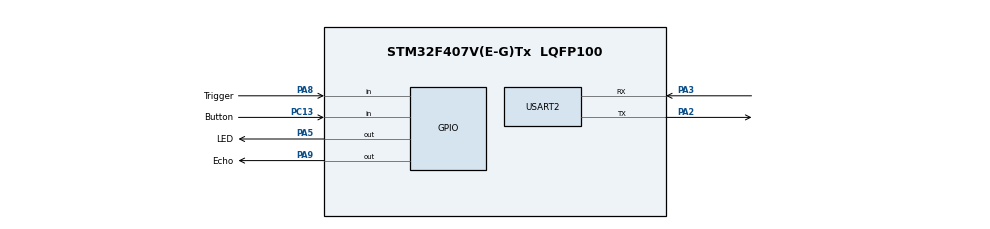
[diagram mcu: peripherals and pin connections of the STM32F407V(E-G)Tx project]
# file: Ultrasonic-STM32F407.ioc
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Mcu.Family=STM32F4
Mcu.Name=STM32F407V(E-G)Tx
Mcu.Package=LQFP100
NVIC.PriorityGroup=NVIC_PRIORITYGROUP_0
PA2.Mode=Asynchronous
PA2.Signal=USART2_TX
PA3.Mode=Asynchronous
PA3.Signal=USART2_RX
PA5.GPIO_Label=LED
PA5.Signal=GPIO_Output
PA8.GPIO_Label=Trigger
PA8.Signal=GPIO_Input
PA9.GPIO_Label=Echo
PA9.Signal=GPIO_Output
PC13-ANTI_TAMP.GPIO_Label=Button
PC13-ANTI_TAMP.Signal=GPIO_Input
ProjectManager.HeapSize=0x200
ProjectManager.StackSize=0x400
ProjectManager.TargetToolchain=STM32CubeIDE
RCC.48MHZClocksFreq_Value=14285714.285714285
RCC.AHBFreq_Value=25000000
RCC.APB1CLKDivider=RCC_HCLK_DIV8
RCC.APB1Freq_Value=3125000
RCC.APB1TimFreq_Value=6250000
RCC.APB2CLKDivider=RCC_HCLK_DIV4
RCC.APB2Freq_Value=6250000
RCC.APB2TimFreq_Value=12500000
RCC.CortexFreq_Value=25000000
RCC.HCLKFreq_Value=25000000
RCC.HSE_VALUE=8000000
RCC.HSI_VALUE=16000000
RCC.PLLM=8
RCC.PLLN=50
RCC.PLLP=RCC_PLLP_DIV4
RCC.PLLQ=7
RCC.SYSCLKFreq_VALUE=25000000
RCC.SYSCLKSource=RCC_SYSCLKSOURCE_PLLCLK
RCC.VCOOutputFreq_Value=100000000
TIM4.Prescaler=24
USART2.VirtualMode=VM_ASYNC
VP_TIM4_VS_ClockSourceINT.Mode=Internal
board=STM32F407G-DISC1

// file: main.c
/* Distance Measurement using Ultrasonic sensor  */

#include "main.h"
#include <string.h>
#include <stdio.h>

#define usTIM	TIM4

TIM_HandleTypeDef htim4;

UART_HandleTypeDef huart2;

#define TRIG_GPIO_Port    GPIOD
#define TRIG_Pin		 GPIO_PIN_0
#define ECHO_GPIO_Port    GPIOD
#define ECHO_Pin 		 GPIO_PIN_0

void SystemClock_Config(void);
static void MX_GPIO_Init(void);
static void MX_TIM4_Init(void);
static void MX_USART2_UART_Init(void);

void usDelay(uint32_t uSec);
//Speed of sound in cm/usec
const float speedOfSound = 0.0343/2;
float distance;

char uartBuf[100];

int main(void)
{

	uint32_t numTicks = 0;

  HAL_Init();

  SystemClock_Config();

  MX_GPIO_Init();
  MX_TIM4_Init();
  MX_USART2_UART_Init();

  while (1)
  {
		//Step 1 Trigger setting low
		HAL_GPIO_WritePin(TRIG_GPIO_Port, TRIG_Pin, GPIO_PIN_RESET);
		usDelay(3);
		//Tigger output sends soundwave 10usec
		HAL_GPIO_WritePin(TRIG_GPIO_Port, TRIG_Pin, GPIO_PIN_SET);
		usDelay(10);

		HAL_GPIO_WritePin(TRIG_GPIO_Port, TRIG_Pin, GPIO_PIN_RESET);

		//Step 2 Wait upto Echo pin reaches High
		while(HAL_GPIO_ReadPin(ECHO_GPIO_Port, ECHO_Pin) == GPIO_PIN_RESET);

		//Step 3 Measuring echo pulse width in usec
		numTicks = 0;
		while(HAL_GPIO_ReadPin(ECHO_GPIO_Port, ECHO_Pin) == GPIO_PIN_SET)
		{
			numTicks++;
			usDelay(2); //2.8usec
		};

		//Step 4 Distance measured in cm
		distance = (numTicks + 0.0f)*2.8*speedOfSound;

		//Step 5 Print distance via uart
		printf(uartBuf, "Distance (cm)  = %.1f\r\n", distance);
		HAL_UART_Transmit(&huart2, (uint8_t *)uartBuf, strlen(uartBuf), 100);

		HAL_Delay(1000);

  }

}

void SystemClock_Config(void)
{
  RCC_OscInitTypeDef RCC_OscInitStruct = {0};
  RCC_ClkInitTypeDef RCC_ClkInitStruct = {0};

  __HAL_RCC_PWR_CLK_ENABLE();
  __HAL_PWR_VOLTAGESCALING_CONFIG(PWR_REGULATOR_VOLTAGE_SCALE2);
  /** Initializes the CPU, AHB and APB busses clocks
  */
  RCC_OscInitStruct.OscillatorType = RCC_OSCILLATORTYPE_HSI;
  RCC_OscInitStruct.HSIState = RCC_HSI_ON;
  RCC_OscInitStruct.HSICalibrationValue = RCC_HSICALIBRATION_DEFAULT;
  RCC_OscInitStruct.PLL.PLLState = RCC_PLL_ON;
  RCC_OscInitStruct.PLL.PLLSource = RCC_PLLSOURCE_HSI;
  RCC_OscInitStruct.PLL.PLLM = 16;
  RCC_OscInitStruct.PLL.PLLN = 336;
  RCC_OscInitStruct.PLL.PLLP = RCC_PLLP_DIV4;
  RCC_OscInitStruct.PLL.PLLQ = 7;
  if (HAL_RCC_OscConfig(&RCC_OscInitStruct) != HAL_OK)
  {
    Error_Handler();
  }
  /** Initializes the CPU, AHB and APB busses clocks
  */
  RCC_ClkInitStruct.ClockType = RCC_CLOCKTYPE_HCLK|RCC_CLOCKTYPE_SYSCLK
                              |RCC_CLOCKTYPE_PCLK1|RCC_CLOCKTYPE_PCLK2;
  RCC_ClkInitStruct.SYSCLKSource = RCC_SYSCLKSOURCE_PLLCLK;
  RCC_ClkInitStruct.AHBCLKDivider = RCC_SYSCLK_DIV1;
  RCC_ClkInitStruct.APB1CLKDivider = RCC_HCLK_DIV2;
  RCC_ClkInitStruct.APB2CLKDivider = RCC_HCLK_DIV1;

  if (HAL_RCC_ClockConfig(&RCC_ClkInitStruct, FLASH_LATENCY_2) != HAL_OK)
  {
    Error_Handler();
  }
}

static void MX_TIM4_Init(void)
{

  TIM_ClockConfigTypeDef sClockSourceConfig = {0};
  TIM_MasterConfigTypeDef sMasterConfig = {0};

  htim4.Instance = TIM4;
  htim4.Init.Prescaler = 84-1;
  htim4.Init.CounterMode = TIM_COUNTERMODE_UP;
  htim4.Init.Period = 0;
  htim4.Init.ClockDivision = TIM_CLOCKDIVISION_DIV1;
  htim4.Init.AutoReloadPreload = TIM_AUTORELOAD_PRELOAD_DISABLE;
  if (HAL_TIM_Base_Init(&htim4) != HAL_OK)
  {
    Error_Handler();
  }
  sClockSourceConfig.ClockSource = TIM_CLOCKSOURCE_INTERNAL;
  if (HAL_TIM_ConfigClockSource(&htim4, &sClockSourceConfig) != HAL_OK)
  {
    Error_Handler();
  }
  sMasterConfig.MasterOutputTrigger = TIM_TRGO_RESET;
  sMasterConfig.MasterSlaveMode = TIM_MASTERSLAVEMODE_DISABLE;
  if (HAL_TIMEx_MasterConfigSynchronization(&htim4, &sMasterConfig) != HAL_OK)
  {
    Error_Handler();
  }

}
static void MX_USART2_UART_Init(void)
{
  huart2.Instance = USART2;
  huart2.Init.BaudRate = 115200;
  huart2.Init.WordLength = UART_WORDLENGTH_8B;
  huart2.Init.StopBits = UART_STOPBITS_1;
  huart2.Init.Parity = UART_PARITY_NONE;
  huart2.Init.Mode = UART_MODE_TX_RX;
  huart2.Init.HwFlowCtl = UART_HWCONTROL_NONE;
  huart2.Init.OverSampling = UART_OVERSAMPLING_16;
  if (HAL_UART_Init(&huart2) != HAL_OK)
  {
    Error_Handler();
  }

}

static void MX_GPIO_Init(void)
{
  GPIO_InitTypeDef GPIO_InitStruct = {0};

  /* GPIO Ports Clock Enable */
  __HAL_RCC_GPIOC_CLK_ENABLE();
  __HAL_RCC_GPIOA_CLK_ENABLE();

  /*Configure GPIO pin Output Level */
  HAL_GPIO_WritePin(GPIOA, LED_Pin|TRIG_Pin, GPIO_PIN_RESET);

  /*Configure GPIO pin : Button_Pin */
  GPIO_InitStruct.Pin = Button_Pin;
  GPIO_InitStruct.Mode = GPIO_MODE_INPUT;
  GPIO_InitStruct.Pull = GPIO_NOPULL;
  HAL_GPIO_Init(Button_GPIO_Port, &GPIO_InitStruct);

  /*Configure GPIO pins : LED_Pin TRIG_Pin */
  GPIO_InitStruct.Pin = LED_Pin|TRIG_Pin;
  GPIO_InitStruct.Mode = GPIO_MODE_OUTPUT_PP;
  GPIO_InitStruct.Pull = GPIO_NOPULL;
  GPIO_InitStruct.Speed = GPIO_SPEED_FREQ_LOW;
  HAL_GPIO_Init(GPIOA, &GPIO_InitStruct);

  /*Configure GPIO pin : ECHO_Pin */
  GPIO_InitStruct.Pin = ECHO_Pin;
  GPIO_InitStruct.Mode = GPIO_MODE_INPUT;
  GPIO_InitStruct.Pull = GPIO_NOPULL;
  HAL_GPIO_Init(ECHO_GPIO_Port, &GPIO_InitStruct);

}

/* USER CODE BEGIN 4 */
void usDelay(uint32_t uSec)
{
	if(uSec < 2) uSec = 2;
	usTIM->ARR = uSec - 1; 	/*sets the value in the auto-reload register*/
	usTIM->EGR = 1; 			/*Re-initialises the timer*/
	usTIM->SR &= ~1; 		//Resets the flag
	usTIM->CR1 |= 1; 		//Enables the counter
	while((usTIM->SR&0x0001) != 1);
	usTIM->SR &= ~(0x0001);
}
/* USER CODE END 4 */

void Error_Handler(void)
{

}

/************************ (C) COPYRIGHT STMicroelectronics *****END OF FILE****/
